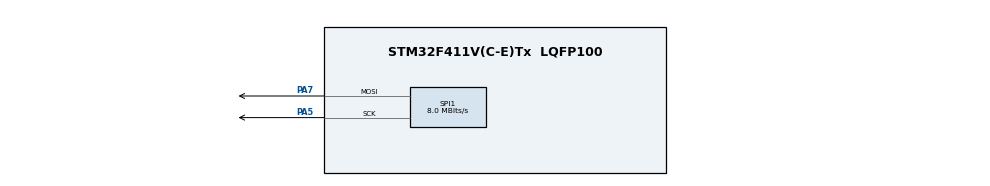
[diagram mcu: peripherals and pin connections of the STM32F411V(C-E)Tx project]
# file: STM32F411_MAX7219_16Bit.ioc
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Mcu.Family=STM32F4
Mcu.Name=STM32F411V(C-E)Tx
Mcu.Package=LQFP100
NVIC.PriorityGroup=NVIC_PRIORITYGROUP_0
PA5.Mode=TX_Only_Simplex_Unidirect_Master
PA5.Signal=SPI1_SCK
PA7.Mode=TX_Only_Simplex_Unidirect_Master
PA7.Signal=SPI1_MOSI
ProjectManager.HeapSize=0x200
ProjectManager.StackSize=0x400
ProjectManager.TargetToolchain=STM32CubeIDE
RCC.48MHZClocksFreq_Value=16000000
RCC.AHBFreq_Value=64000000
RCC.APB1CLKDivider=RCC_HCLK_DIV2
RCC.APB1Freq_Value=32000000
RCC.APB1TimFreq_Value=64000000
RCC.APB2CLKDivider=RCC_HCLK_DIV4
RCC.APB2Freq_Value=16000000
RCC.APB2TimFreq_Value=32000000
RCC.CortexFreq_Value=64000000
RCC.HCLKFreq_Value=64000000
RCC.HSE_VALUE=8000000
RCC.HSI_VALUE=16000000
RCC.LSE_VALUE=32768
RCC.PLLI2SM=5
RCC.PLLI2SN=200
RCC.PLLM=8
RCC.PLLN=64
RCC.PLLQ=8
RCC.SYSCLKFreq_VALUE=64000000
RCC.SYSCLKSource=RCC_SYSCLKSOURCE_PLLCLK
RCC.VCOOutputFreq_Value=128000000
SPI1.CalculateBaudRate=8.0 MBits/s
SPI1.DataSize=SPI_DATASIZE_8BIT
SPI1.Direction=SPI_DIRECTION_2LINES
SPI1.Mode=SPI_MODE_MASTER
SPI1.VirtualType=VM_MASTER
board=STM32F411E-DISCO

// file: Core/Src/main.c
/* USER CODE BEGIN Header */
/**
  ******************************************************************************
  * @file           : main.c
  * @brief          : Main program body
  ******************************************************************************
  * @attention
  *
  * Copyright (c) 2026 STMicroelectronics.
  * All rights reserved.
  *
  * This software is licensed under terms that can be found in the LICENSE file
  * in the root directory of this software component.
  * If no LICENSE file comes with this software, it is provided AS-IS.
  *
  ******************************************************************************
  */
/* USER CODE END Header */
#include "main.h"

/* USER CODE BEGIN Includes */

#include "led_driver.h"

/* USER CODE END Includes */

/* USER CODE BEGIN PD */

#define MAX7219_CS_LOW() HAL_GPIO_WritePin(GPIOA,GPIO_PIN_4,GPIO_PIN_RESET)
#define MAX7219_CS_HIGH() HAL_GPIO_WritePin(GPIOA,GPIO_PIN_4,GPIO_PIN_SET)

/* USER CODE END PD */

SPI_HandleTypeDef hspi1;

void SystemClock_Config(void);
static void MX_GPIO_Init(void);
static void MX_SPI1_Init(void);
/* USER CODE BEGIN PFP */

void MAX7219_Write(uint8_t reg,uint8_t data);
void MAX7219_Init(void);
void MAX7219_Clear(void);

/* USER CODE END PFP */

int main(void)
{

  /* MCU Configuration--------------------------------------------------------*/

  /* Reset of all peripherals, Initializes the Flash interface and the Systick. */
  HAL_Init();

  /* USER CODE BEGIN Init */

  led_Init();

  /* USER CODE END Init */

  /* Configure the system clock */
  SystemClock_Config();

  /* Initialize all configured peripherals */
  MX_GPIO_Init();
  MX_SPI1_Init();
  /* USER CODE BEGIN 2 */

  MAX7219_Init();
  GPIOD->BSRR |=GPIO_BSRR_BS15;

  /* USER CODE END 2 */

  /* Infinite loop */
  while (1)
  {

  }
}

void SystemClock_Config(void) {
	RCC_OscInitTypeDef RCC_OscInitStruct = { 0 };
	RCC_ClkInitTypeDef RCC_ClkInitStruct = { 0 };

	/** Configure the main internal regulator output voltage
	 */
	__HAL_RCC_PWR_CLK_ENABLE();
	__HAL_PWR_VOLTAGESCALING_CONFIG(PWR_REGULATOR_VOLTAGE_SCALE1);

	/** Initializes the RCC Oscillators according to the specified parameters
	 * in the RCC_OscInitTypeDef structure.
	 */
	RCC_OscInitStruct.OscillatorType = RCC_OSCILLATORTYPE_HSI;
	RCC_OscInitStruct.HSIState = RCC_HSI_ON;
	RCC_OscInitStruct.HSICalibrationValue = RCC_HSICALIBRATION_DEFAULT;
	RCC_OscInitStruct.PLL.PLLState = RCC_PLL_ON;
  RCC_OscInitStruct.PLL.PLLSource = RCC_PLLSOURCE_HSI;
  RCC_OscInitStruct.PLL.PLLM = 8;
  RCC_OscInitStruct.PLL.PLLN = 192;
  RCC_OscInitStruct.PLL.PLLP = RCC_PLLP_DIV4;
  RCC_OscInitStruct.PLL.PLLQ = 8;
  if (HAL_RCC_OscConfig(&RCC_OscInitStruct) != HAL_OK)
  {
    Error_Handler();
  }

  /** Initializes the CPU, AHB and APB buses clocks
  */
  RCC_ClkInitStruct.ClockType = RCC_CLOCKTYPE_HCLK|RCC_CLOCKTYPE_SYSCLK
                              |RCC_CLOCKTYPE_PCLK1|RCC_CLOCKTYPE_PCLK2;
  RCC_ClkInitStruct.SYSCLKSource = RCC_SYSCLKSOURCE_PLLCLK;
  RCC_ClkInitStruct.AHBCLKDivider = RCC_SYSCLK_DIV1;
  RCC_ClkInitStruct.APB1CLKDivider = RCC_HCLK_DIV4;
  RCC_ClkInitStruct.APB2CLKDivider = RCC_HCLK_DIV2;

  if (HAL_RCC_ClockConfig(&RCC_ClkInitStruct, FLASH_LATENCY_3) != HAL_OK)
  {
    Error_Handler();
  }
}

static void MX_SPI1_Init(void)
{

  /* SPI1 parameter configuration*/
  hspi1.Instance = SPI1;
  hspi1.Init.Mode = SPI_MODE_MASTER;
  hspi1.Init.Direction = SPI_DIRECTION_2LINES;
  hspi1.Init.DataSize = SPI_DATASIZE_8BIT;
  hspi1.Init.CLKPolarity = SPI_POLARITY_LOW;
  hspi1.Init.CLKPhase = SPI_PHASE_1EDGE;
  hspi1.Init.NSS = SPI_NSS_SOFT;
  hspi1.Init.BaudRatePrescaler = SPI_BAUDRATEPRESCALER_2;
  hspi1.Init.FirstBit = SPI_FIRSTBIT_MSB;
  hspi1.Init.TIMode = SPI_TIMODE_DISABLE;
  hspi1.Init.CRCCalculation = SPI_CRCCALCULATION_DISABLE;
  hspi1.Init.CRCPolynomial = 10;
  if (HAL_SPI_Init(&hspi1) != HAL_OK)
  {
    Error_Handler();
  }

}

static void MX_GPIO_Init(void)
{

  /* GPIO Ports Clock Enable */
  __HAL_RCC_GPIOA_CLK_ENABLE();

}

/* USER CODE BEGIN 4 */

void MAX7219_Write(uint8_t reg, uint8_t data){

	MAX7219_CS_LOW();

	uint8_t packet[2]={reg,data};

	HAL_SPI_Transmit(&hspi1, packet, 2, HAL_MAX_DELAY);

	MAX7219_CS_HIGH();

}

void MAX7219_Init(void){
	MAX7219_Write(0x0C, 0x01);
	MAX7219_Write(0x09, 0x00);
	MAX7219_Write(0x0A, 0x00);
	MAX7219_Write(0x0B, 0x07);
	MAX7219_Write(0x0F, 0x00);

	//MAX7219_Write(0x01, 0x00);
	MAX7219_Clear();

	MAX7219_Write(0x01, 0xFF);

}

void MAX7219_Clear(void){
	  for(uint8_t row=0; row<8; row++){

		  MAX7219_Write(row+1, 0x00);
	  }
 }

/* USER CODE END 4 */

void Error_Handler(void)
{
  __disable_irq();
  while (1)
  {
  }
}
